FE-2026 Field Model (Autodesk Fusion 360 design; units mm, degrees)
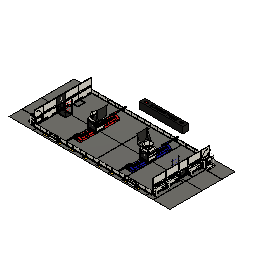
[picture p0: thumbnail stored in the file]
description: STEP AP242 Edition 2
part number: FE-2026: REBUILT
description: GE-26900: FUEL
part number: GE-26900: FUEL
description: BLOCK CAD: SCORING TABLE
part number: BLOCK CAD: SCORING TABLE
description: 100in Long 2in Wide White Gaff Tape
part number: 100in Long 2in Wide White Gaff Tape
description: FE-2026-01: Playing Field Carpet
part number: FE-2026-01: Playing Field Carpet
description: 17.625in Long 2in Wide Red Gaff Tape
part number: 17.625in Long 2in Wide Red Gaff Tape
description: 17.625in Long 2in Wide Blue Gaff Tape
part number: 17.625in Long 2in Wide Blue Gaff Tape
description: 317.187in Long 2in Wide Red Gaff Tape
part number: 317.187in Long 2in Wide Red Gaff Tape
description: 316.188in Long 2in Wide White Gaff Tape
part number: 316.188in Long 2in Wide White Gaff Tape
description: 289in Long 2in Wide White Gaff Tape
part number: 289in Long 2in Wide White Gaff Tape
base_feature "Base Feature1"
base_feature "Base Feature1"
base_feature "Base Feature1"
base_feature "Base Feature1"
base_feature "Base Feature1"
base_feature "Base Feature1"
base_feature "Base Feature1"
base_feature "Base Feature1"
base_feature "Base Feature1"
base_feature "Base Feature1"
base_feature "Base Feature1"
base_feature "Base Feature1"
base_feature "Base Feature1"
base_feature "Base Feature1"
base_feature "Base Feature1"
base_feature "Base Feature1"
base_feature "Base Feature1"
base_feature "Base Feature1"
base_feature "Base Feature1"
base_feature "Base Feature1"
base_feature "Base Feature1"
base_feature "Base Feature1"
base_feature "Base Feature1"
base_feature "Base Feature1"
base_feature "Base Feature1"
base_feature "Base Feature1"
base_feature "Base Feature1"
base_feature "Base Feature1"
base_feature "Base Feature1"
base_feature "Base Feature1"
base_feature "Base Feature1"
base_feature "Base Feature1"
base_feature "Base Feature1"
base_feature "Base Feature1"
base_feature "Base Feature1"
base_feature "Base Feature1"
base_feature "Base Feature1"
base_feature "Base Feature1"
base_feature "Base Feature1"
base_feature "Base Feature1"
base_feature "Base Feature1"
base_feature "Base Feature1"
base_feature "Base Feature1"
base_feature "Base Feature1"
base_feature "Base Feature1"
base_feature "Base Feature1"
base_feature "Base Feature1"
base_feature "Base Feature1"
base_feature "Base Feature1"
base_feature "Base Feature1"
base_feature "Base Feature1"
base_feature "Base Feature1"
base_feature "Base Feature1"
base_feature "Base Feature1"
base_feature "Base Feature1"
base_feature "Base Feature1"
base_feature "Base Feature1"
base_feature "Base Feature1"
base_feature "Base Feature1"
base_feature "Base Feature1"
base_feature "Base Feature1"
base_feature "Base Feature1"
base_feature "Base Feature1"
base_feature "Base Feature1"
base_feature "Base Feature1"
base_feature "Base Feature1"
base_feature "Base Feature1"
base_feature "Base Feature1"
base_feature "Base Feature1"
base_feature "Base Feature1"
base_feature "Base Feature1"
base_feature "Base Feature1"
base_feature "Base Feature1"
base_feature "Base Feature1"
base_feature "Base Feature1"
base_feature "Base Feature1"
base_feature "Base Feature1"
base_feature "Base Feature1"
base_feature "Base Feature1"
base_feature "Base Feature1"
base_feature "Base Feature1"
base_feature "Base Feature1"
base_feature "Base Feature1"
base_feature "Base Feature1"
base_feature "Base Feature1"
base_feature "Base Feature1"
base_feature "Base Feature1"
base_feature "Base Feature1"
base_feature "Base Feature1"
base_feature "Base Feature1"
base_feature "Base Feature1"
base_feature "Base Feature1"
base_feature "Base Feature1"
base_feature "Base Feature1"
base_feature "Base Feature1"
base_feature "Base Feature1"
base_feature "Base Feature1"
base_feature "Base Feature1"
base_feature "Base Feature1"
base_feature "Base Feature1"
base_feature "Base Feature1"
base_feature "Base Feature1"
base_feature "Base Feature1"
base_feature "Base Feature1"
base_feature "Base Feature1"
base_feature "Base Feature1"
base_feature "Base Feature1"
base_feature "Base Feature1"
base_feature "Base Feature1"
base_feature "Base Feature1"
base_feature "Base Feature1"
base_feature "Base Feature1"
base_feature "Base Feature1"
base_feature "Base Feature1"
base_feature "Base Feature1"
base_feature "Base Feature1"
base_feature "Base Feature1"
base_feature "Base Feature1"
base_feature "Base Feature1"
base_feature "Base Feature1"
base_feature "Base Feature1"
base_feature "Base Feature1"
base_feature "Base Feature1"
base_feature "Base Feature1"
base_feature "Base Feature1"
base_feature "Base Feature1"
base_feature "Base Feature1"
base_feature "Base Feature1"
base_feature "Base Feature1"
base_feature "Base Feature1"
base_feature "Base Feature1"
base_feature "Base Feature1"
base_feature "Base Feature1"
base_feature "Base Feature1"
base_feature "Base Feature1"
base_feature "Base Feature1"
base_feature "Base Feature1"
base_feature "Base Feature1"
base_feature "Base Feature1"
base_feature "Base Feature1"
base_feature "Base Feature1"
base_feature "Base Feature1"
base_feature "Base Feature1"
base_feature "Base Feature1"
base_feature "Base Feature1"
base_feature "Base Feature1"
base_feature "Base Feature1"
base_feature "Base Feature1"
base_feature "Base Feature1"
base_feature "Base Feature1"
base_feature "Base Feature1"
base_feature "Base Feature1"
base_feature "Base Feature1"
base_feature "Base Feature1"
base_feature "Base Feature1"
base_feature "Base Feature1"
base_feature "Base Feature1"
base_feature "Base Feature1"
base_feature "Base Feature1"
base_feature "Base Feature1"
base_feature "Base Feature1"
base_feature "Base Feature1"
base_feature "Base Feature1"
base_feature "Base Feature1"
base_feature "Base Feature1"
base_feature "Base Feature1"
base_feature "Base Feature1"
base_feature "Base Feature1"
base_feature "Base Feature1"
base_feature "Base Feature1"
base_feature "Base Feature1"
base_feature "Base Feature1"
base_feature "Base Feature1"
base_feature "Base Feature1"
base_feature "Base Feature1"
base_feature "Base Feature1"
base_feature "Base Feature1"
base_feature "Base Feature1"
base_feature "Base Feature1"
base_feature "Base Feature1"
base_feature "Base Feature1"
base_feature "Base Feature1"
base_feature "Base Feature1"
base_feature "Base Feature1"
base_feature "Base Feature1"
base_feature "Base Feature1"
base_feature "Base Feature1"
base_feature "Base Feature1"
base_feature "Base Feature1"
base_feature "Base Feature1"
base_feature "Base Feature1"
base_feature "Base Feature1"
base_feature "Base Feature1"
base_feature "Base Feature1"
base_feature "Base Feature1"
base_feature "Base Feature1"
base_feature "Base Feature1"
base_feature "Base Feature1"
base_feature "Base Feature1"
base_feature "Base Feature1"
base_feature "Base Feature1"
base_feature "Base Feature1"
base_feature "Base Feature1"
base_feature "Base Feature1"
base_feature "Base Feature1"
base_feature "Base Feature1"
base_feature "Base Feature1"
base_feature "Base Feature1"
base_feature "Base Feature1"
base_feature "Base Feature1"
base_feature "Base Feature1"
base_feature "Base Feature1"
base_feature "Base Feature1"
base_feature "Base Feature1"
base_feature "Base Feature1"
base_feature "Base Feature1"
base_feature "Base Feature1"
base_feature "Base Feature1"
base_feature "Base Feature1"
base_feature "Base Feature1"
base_feature "Base Feature1"
base_feature "Base Feature1"
base_feature "Base Feature1"
base_feature "Base Feature1"
base_feature "Base Feature1"
base_feature "Base Feature1"
base_feature "Base Feature1"
base_feature "Base Feature1"
base_feature "Base Feature1"
base_feature "Base Feature1"
base_feature "Base Feature1"
base_feature "Base Feature1"
base_feature "Base Feature1"
base_feature "Base Feature1"
base_feature "Base Feature1"
base_feature "Base Feature1"
base_feature "Base Feature1"
base_feature "Base Feature1"
base_feature "Base Feature1"
base_feature "Base Feature1"
base_feature "Base Feature1"
base_feature "Base Feature1"
base_feature "Base Feature1"
base_feature "Base Feature1"
base_feature "Base Feature1"
base_feature "Base Feature1"
base_feature "Base Feature1"
base_feature "Base Feature1"
base_feature "Base Feature1"
base_feature "Base Feature1"
base_feature "Base Feature1"
base_feature "Base Feature1"
base_feature "Base Feature1"
base_feature "Base Feature1"
base_feature "Base Feature1"
base_feature "Base Feature1"
base_feature "Base Feature1"
base_feature "Base Feature1"
base_feature "Base Feature1"
base_feature "Base Feature1"
base_feature "Base Feature1"
base_feature "Base Feature1"
base_feature "Base Feature1"
base_feature "Base Feature1"
base_feature "Base Feature1"
base_feature "Base Feature1"
base_feature "Base Feature1"
base_feature "Base Feature1"
base_feature "Base Feature1"
base_feature "Base Feature1"
base_feature "Base Feature1"
base_feature "Base Feature1"
base_feature "Base Feature1"
base_feature "Base Feature1"
base_feature "Base Feature1"
base_feature "Base Feature1"
base_feature "Base Feature1"
base_feature "Base Feature1"
base_feature "Base Feature1"
base_feature "Base Feature1"
base_feature "Base Feature1"
base_feature "Base Feature1"
base_feature "Base Feature1"
base_feature "Base Feature1"
base_feature "Base Feature1"
base_feature "Base Feature1"
base_feature "Base Feature1"
base_feature "Base Feature1"
base_feature "Base Feature1"
base_feature "Base Feature1"
base_feature "Base Feature1"
base_feature "Base Feature1"
base_feature "Base Feature1"
base_feature "Base Feature1"
base_feature "Base Feature1"
base_feature "Base Feature1"
base_feature "Base Feature1"
base_feature "Base Feature1"
base_feature "Base Feature1"
base_feature "Base Feature1"
base_feature "Base Feature1"
base_feature "Base Feature1"
base_feature "Base Feature1"
base_feature "Base Feature1"
base_feature "Base Feature1"
base_feature "Base Feature1"
base_feature "Base Feature1"
base_feature "Base Feature1"
base_feature "Base Feature1"
base_feature "Base Feature1"
base_feature "Base Feature1"
base_feature "Base Feature1"
base_feature "Base Feature1"
base_feature "Base Feature1"
base_feature "Base Feature1"
base_feature "Base Feature1"
base_feature "Base Feature1"
base_feature "Base Feature1"
base_feature "Base Feature1"
base_feature "Base Feature1"
base_feature "Base Feature1"
base_feature "Base Feature1"
base_feature "Base Feature1"
base_feature "Base Feature1"
base_feature "Base Feature1"
base_feature "Base Feature1"
base_feature "Base Feature1"
base_feature "Base Feature1"
base_feature "Base Feature1"
base_feature "Base Feature1"
base_feature "Base Feature1"
base_feature "Base Feature1"
base_feature "Base Feature1"
base_feature "Base Feature1"
base_feature "Base Feature1"
base_feature "Base Feature1"
base_feature "Base Feature1"
base_feature "Base Feature1"
base_feature "Base Feature1"
base_feature "Base Feature1"
base_feature "Base Feature1"
base_feature "Base Feature1"
base_feature "Base Feature1"
base_feature "Base Feature1"
base_feature "Base Feature1"
base_feature "Base Feature1"
base_feature "Base Feature1"
base_feature "Base Feature1"
base_feature "Base Feature1"
base_feature "Base Feature1"
base_feature "Base Feature1"
base_feature "Base Feature1"
base_feature "Base Feature1"
base_feature "Base Feature1"
base_feature "Base Feature1"
base_feature "Base Feature1"
base_feature "Base Feature1"
base_feature "Base Feature1"
base_feature "Base Feature1"
base_feature "Base Feature1"
base_feature "Base Feature1"
base_feature "Base Feature1"
base_feature "Base Feature1"
base_feature "Base Feature1"
base_feature "Base Feature1"
base_feature "Base Feature1"
base_feature "Base Feature1"
base_feature "Base Feature1"
base_feature "Base Feature1"
base_feature "Base Feature1"
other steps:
create_component "CreateComponent1"
create_component "CreateComponent2"
create_component "CreateComponent3"
create_component "CreateComponent4"
create_component "CreateComponent5"
create_component "CreateComponent6"
create_component "CreateComponent7"
create_component "CreateComponent8"
create_component "CreateComponent9"
create_component "CreateComponent10"
create_component "CreateComponent1"
create_component "CreateComponent1"
create_component "CreateComponent2"
create_component "CreateComponent2"
create_component "CreateComponent3"
create_component "CreateComponent11"
create_component "CreateComponent1"
create_component "CreateComponent1"
create_component "CreateComponent2"
create_component "CreateComponent12"
create_component "CreateComponent13"
create_component "CreateComponent1"
create_component "CreateComponent2"
create_component "CreateComponent3"
create_component "CreateComponent4"
create_component "CreateComponent5"
create_component "CreateComponent6"
create_component "CreateComponent7"
create_component "CreateComponent8"
create_component "CreateComponent9"
create_component "CreateComponent10"
create_component "CreateComponent11"
create_component "CreateComponent12"
create_component "CreateComponent13"
create_component "CreateComponent14"
create_component "CreateComponent15"
create_component "CreateComponent16"
create_component "CreateComponent17"
create_component "CreateComponent1"
create_component "CreateComponent18"
create_component "CreateComponent19"
create_component "CreateComponent20"
create_component "CreateComponent21"
create_component "CreateComponent22"
create_component "CreateComponent23"
create_component "CreateComponent24"
create_component "CreateComponent25"
create_component "CreateComponent26"
create_component "CreateComponent27"
create_component "CreateComponent28"
create_component "CreateComponent1"
create_component "CreateComponent2"
create_component "CreateComponent29"
create_component "CreateComponent1"
create_component "CreateComponent2"
create_component "CreateComponent3"
create_component "CreateComponent30"
create_component "CreateComponent1"
create_component "CreateComponent2"
create_component "CreateComponent31"
create_component "CreateComponent32"
create_component "CreateComponent33"
create_component "CreateComponent1"
create_component "CreateComponent2"
create_component "CreateComponent34"
create_component "CreateComponent35"
create_component "CreateComponent1"
create_component "CreateComponent2"
create_component "CreateComponent3"
create_component "CreateComponent4"
create_component "CreateComponent36"
create_component "CreateComponent1"
create_component "CreateComponent2"
create_component "CreateComponent3"
create_component "CreateComponent4"
create_component "CreateComponent37"
create_component "CreateComponent1"
create_component "CreateComponent14"
create_component "CreateComponent1"
create_component "CreateComponent2"
create_component "CreateComponent3"
create_component "CreateComponent1"
create_component "CreateComponent2"
create_component "CreateComponent3"
create_component "CreateComponent4"
create_component "CreateComponent1"
create_component "CreateComponent2"
create_component "CreateComponent5"
create_component "CreateComponent6"
create_component "CreateComponent7"
create_component "CreateComponent8"
create_component "CreateComponent9"
create_component "CreateComponent10"
create_component "CreateComponent1"
create_component "CreateComponent11"
create_component "CreateComponent12"
create_component "CreateComponent1"
create_component "CreateComponent4"
create_component "CreateComponent1"
create_component "CreateComponent2"
create_component "CreateComponent3"
create_component "CreateComponent4"
create_component "CreateComponent5"
create_component "CreateComponent15"
create_component "CreateComponent1"
create_component "CreateComponent2"
create_component "CreateComponent3"
create_component "CreateComponent4"
create_component "CreateComponent5"
create_component "CreateComponent6"
create_component "CreateComponent1"
create_component "CreateComponent2"
create_component "CreateComponent7"
create_component "CreateComponent8"
create_component "CreateComponent9"
create_component "CreateComponent1"
create_component "CreateComponent2"
create_component "CreateComponent10"
create_component "CreateComponent1"
create_component "CreateComponent11"
create_component "CreateComponent1"
create_component "CreateComponent2"
create_component "CreateComponent12"
create_component "CreateComponent13"
create_component "CreateComponent1"
create_component "CreateComponent2"
create_component "CreateComponent3"
create_component "CreateComponent4"
create_component "CreateComponent14"
create_component "CreateComponent15"
create_component "CreateComponent16"
create_component "CreateComponent1"
create_component "CreateComponent2"
create_component "CreateComponent3"
create_component "CreateComponent17"
create_component "CreateComponent18"
create_component "CreateComponent16"
create_component "CreateComponent1"
create_component "CreateComponent2"
create_component "CreateComponent1"
create_component "CreateComponent2"
create_component "CreateComponent3"
create_component "CreateComponent4"
create_component "CreateComponent5"
create_component "CreateComponent3"
create_component "CreateComponent1"
create_component "CreateComponent2"
create_component "CreateComponent3"
create_component "CreateComponent4"
create_component "CreateComponent5"
create_component "CreateComponent17"
create_component "CreateComponent1"
create_component "CreateComponent2"
create_component "CreateComponent3"
create_component "CreateComponent4"
create_component "CreateComponent5"
create_component "CreateComponent6"
create_component "CreateComponent7"
create_component "CreateComponent1"
create_component "CreateComponent8"
create_component "CreateComponent9"
create_component "CreateComponent10"
create_component "CreateComponent1"
create_component "CreateComponent11"
create_component "CreateComponent12"
create_component "CreateComponent13"
create_component "CreateComponent18"
create_component "CreateComponent1"
create_component "CreateComponent2"
create_component "CreateComponent3"
create_component "CreateComponent4"
create_component "CreateComponent5"
create_component "CreateComponent6"
create_component "CreateComponent7"
create_component "CreateComponent8"
create_component "CreateComponent9"
create_component "CreateComponent10"
create_component "CreateComponent11"
create_component "CreateComponent12"
create_component "CreateComponent13"
create_component "CreateComponent14"
create_component "CreateComponent15"
create_component "CreateComponent16"
create_component "CreateComponent17"
create_component "CreateComponent18"
create_component "CreateComponent19"
create_component "CreateComponent20"
create_component "CreateComponent21"
create_component "CreateComponent22"
create_component "CreateComponent1"
create_component "CreateComponent23"
create_component "CreateComponent24"
create_component "CreateComponent25"
create_component "CreateComponent26"
create_component "CreateComponent27"
create_component "CreateComponent28"
create_component "CreateComponent29"
create_component "CreateComponent30"
create_component "CreateComponent31"
create_component "CreateComponent1"
create_component "CreateComponent32"
create_component "CreateComponent1"
create_component "CreateComponent33"
create_component "CreateComponent1"
create_component "CreateComponent34"
create_component "CreateComponent35"
create_component "CreateComponent1"
create_component "CreateComponent36"
create_component "CreateComponent1"
create_component "CreateComponent2"
create_component "CreateComponent3"
create_component "CreateComponent4"
create_component "CreateComponent37"
create_component "CreateComponent38"
create_component "CreateComponent39"
create_component "CreateComponent40"
create_component "CreateComponent41"
create_component "CreateComponent1"
create_component "CreateComponent42"
create_component "CreateComponent43"
create_component "CreateComponent1"
create_component "CreateComponent44"
create_component "CreateComponent45"
create_component "CreateComponent46"
create_component "CreateComponent1"
create_component "CreateComponent47"
create_component "CreateComponent48"
create_component "CreateComponent49"
create_component "CreateComponent1"
create_component "CreateComponent50"
create_component "CreateComponent51"
create_component "CreateComponent1"
create_component "CreateComponent2"
create_component "CreateComponent52"
create_component "CreateComponent1"
create_component "CreateComponent53"
create_component "CreateComponent54"
create_component "CreateComponent1"
create_component "CreateComponent55"
create_component "CreateComponent1"
create_component "CreateComponent56"
create_component "CreateComponent1"
create_component "CreateComponent57"
create_component "CreateComponent1"
create_component "CreateComponent2"
create_component "CreateComponent3"
create_component "CreateComponent4"
create_component "CreateComponent58"
create_component "CreateComponent1"
create_component "CreateComponent59"
create_component "CreateComponent1"
create_component "CreateComponent60"
create_component "CreateComponent1"
create_component "CreateComponent61"
create_component "CreateComponent62"
create_component "CreateComponent63"
create_component "CreateComponent64"
create_component "CreateComponent1"
create_component "CreateComponent65"
create_component "CreateComponent1"
create_component "CreateComponent66"
create_component "CreateComponent67"
create_component "CreateComponent68"
create_component "CreateComponent69"
create_component "CreateComponent70"
create_component "CreateComponent71"
create_component "CreateComponent72"
create_component "CreateComponent73"
create_component "CreateComponent74"
create_component "CreateComponent75"
create_component "CreateComponent1"
create_component "CreateComponent2"
create_component "CreateComponent3"
create_component "CreateComponent4"
create_component "CreateComponent5"
create_component "CreateComponent6"
create_component "CreateComponent7"
create_component "CreateComponent8"
create_component "CreateComponent9"
create_component "CreateComponent10"
create_component "CreateComponent11"
create_component "CreateComponent12"
create_component "CreateComponent13"
create_component "CreateComponent14"
create_component "CreateComponent15"
create_component "CreateComponent16"
create_component "CreateComponent1"
create_component "CreateComponent2"
create_component "CreateComponent17"
create_component "CreateComponent18"
create_component "CreateComponent19"
create_component "CreateComponent20"
create_component "CreateComponent21"
create_component "CreateComponent22"
create_component "CreateComponent23"
create_component "CreateComponent1"
create_component "CreateComponent24"
create_component "CreateComponent25"
create_component "CreateComponent26"
create_component "CreateComponent27"
create_component "CreateComponent28"
create_component "CreateComponent29"
create_component "CreateComponent30"
create_component "CreateComponent31"
create_component "CreateComponent32"
create_component "CreateComponent33"
create_component "CreateComponent34"
create_component "CreateComponent35"
create_component "CreateComponent36"
create_component "CreateComponent37"
create_component "CreateComponent38"
create_component "CreateComponent39"
create_component "CreateComponent1"
create_component "CreateComponent40"
create_component "CreateComponent41"
create_component "CreateComponent42"
create_component "CreateComponent1"
create_component "CreateComponent43"
create_component "CreateComponent44"
create_component "CreateComponent45"
create_component "CreateComponent46"
create_component "CreateComponent47"
create_component "CreateComponent1"
create_component "CreateComponent2"
create_component "CreateComponent3"
create_component "CreateComponent4"
create_component "CreateComponent48"
create_component "CreateComponent1"
create_component "CreateComponent49"
create_component "CreateComponent50"
create_component "CreateComponent51"
create_component "CreateComponent52"
create_component "CreateComponent1"
create_component "CreateComponent2"
create_component "CreateComponent3"
create_component "CreateComponent53"
create_component "CreateComponent54"
create_component "CreateComponent1"
create_component "CreateComponent55"
create_component "CreateComponent1"
create_component "CreateComponent2"
create_component "CreateComponent3"
create_component "CreateComponent4"
create_component "CreateComponent5"
create_component "CreateComponent6"
create_component "CreateComponent7"
create_component "CreateComponent8"
create_component "CreateComponent9"
create_component "CreateComponent10"
create_component "CreateComponent11"
create_component "CreateComponent12"
create_component "CreateComponent13"
create_component "CreateComponent14"
create_component "CreateComponent15"
create_component "CreateComponent16"
create_component "CreateComponent17"
create_component "CreateComponent18"
create_component "CreateComponent19"
create_component "CreateComponent20"
create_component "CreateComponent21"
create_component "CreateComponent22"
create_component "CreateComponent23"
create_component "CreateComponent56"
create_component "CreateComponent57"
create_component "CreateComponent58"
create_component "CreateComponent59"
create_component "CreateComponent60"
create_component "CreateComponent1"
create_component "CreateComponent2"
create_component "CreateComponent61"
create_component "CreateComponent62"
create_component "CreateComponent63"
create_component "CreateComponent1"
create_component "CreateComponent76"
create_component "CreateComponent1"
create_component "CreateComponent2"
create_component "CreateComponent3"
create_component "CreateComponent4"
create_component "CreateComponent77"
create_component "CreateComponent78"
create_component "CreateComponent19"
create_component "CreateComponent1"
create_component "CreateComponent1"
create_component "CreateComponent2"
create_component "CreateComponent3"
create_component "CreateComponent4"
create_component "CreateComponent5"
create_component "CreateComponent2"
create_component "CreateComponent1"
create_component "CreateComponent2"
create_component "CreateComponent3"
create_component "CreateComponent4"
create_component "CreateComponent5"
create_component "CreateComponent20"
create_component "CreateComponent1"
create_component "CreateComponent1"
create_component "CreateComponent2"
create_component "CreateComponent3"
create_component "CreateComponent4"
create_component "CreateComponent5"
create_component "CreateComponent2"
create_component "CreateComponent1"
create_component "CreateComponent2"
create_component "CreateComponent3"
create_component "CreateComponent4"
create_component "CreateComponent5"
create_component "CreateComponent21"
create_component "CreateComponent1"
create_component "CreateComponent1"
create_component "CreateComponent2"
create_component "CreateComponent3"
create_component "CreateComponent1"
create_component "CreateComponent4"
create_component "CreateComponent5"
create_component "CreateComponent6"
create_component "CreateComponent1"
create_component "CreateComponent7"
create_component "CreateComponent8"
create_component "CreateComponent1"
create_component "CreateComponent9"
create_component "CreateComponent10"
create_component "CreateComponent11"
create_component "CreateComponent12"
create_component "CreateComponent1"
create_component "CreateComponent13"
create_component "CreateComponent14"
create_component "CreateComponent15"
create_component "CreateComponent16"
create_component "CreateComponent17"
create_component "CreateComponent1"
create_component "CreateComponent18"
create_component "CreateComponent19"
create_component "CreateComponent20"
create_component "CreateComponent21"
create_component "CreateComponent22"
create_component "CreateComponent23"
create_component "CreateComponent1"
create_component "CreateComponent24"
create_component "CreateComponent25"
create_component "CreateComponent26"
create_component "CreateComponent27"
create_component "CreateComponent28"
create_component "CreateComponent29"
create_component "CreateComponent30"
create_component "CreateComponent31"
create_component "CreateComponent32"
create_component "CreateComponent1"
create_component "CreateComponent33"
create_component "CreateComponent34"
create_component "CreateComponent35"
create_component "CreateComponent36"
create_component "CreateComponent37"
create_component "CreateComponent1"
create_component "CreateComponent2"
create_component "CreateComponent3"
create_component "CreateComponent4"
create_component "CreateComponent5"
create_component "CreateComponent6"
create_component "CreateComponent7"
create_component "CreateComponent8"
create_component "CreateComponent9"
create_component "CreateComponent10"
create_component "CreateComponent11"
create_component "CreateComponent12"
create_component "CreateComponent13"
create_component "CreateComponent14"
create_component "CreateComponent15"
create_component "CreateComponent16"
create_component "CreateComponent17"
create_component "CreateComponent18"
create_component "CreateComponent19"
create_component "CreateComponent20"
create_component "CreateComponent21"
create_component "CreateComponent22"
create_component "CreateComponent23"
create_component "CreateComponent24"
create_component "CreateComponent25"
create_component "CreateComponent26"
create_component "CreateComponent27"
create_component "CreateComponent28"
create_component "CreateComponent29"
create_component "CreateComponent30"
create_component "CreateComponent31"
create_component "CreateComponent38"
create_component "CreateComponent39"
create_component "CreateComponent22"
create_component "CreateComponent1"
create_component "CreateComponent1"
create_component "CreateComponent2"
create_component "CreateComponent3"
create_component "CreateComponent4"
create_component "CreateComponent5"
create_component "CreateComponent1"
create_component "CreateComponent2"
create_component "CreateComponent6"
create_component "CreateComponent7"
create_component "CreateComponent8"
create_component "CreateComponent1"
create_component "CreateComponent2"
create_component "CreateComponent3"
create_component "CreateComponent4"
create_component "CreateComponent9"
create_component "CreateComponent1"
create_component "CreateComponent10"
create_component "CreateComponent1"
create_component "CreateComponent11"
create_component "CreateComponent12"
create_component "CreateComponent13"
create_component "CreateComponent14"
create_component "CreateComponent1"
create_component "CreateComponent15"
create_component "CreateComponent16"
create_component "CreateComponent1"
create_component "CreateComponent2"
create_component "CreateComponent3"
create_component "CreateComponent4"
create_component "CreateComponent5"
create_component "CreateComponent6"
create_component "CreateComponent17"
create_component "CreateComponent18"
create_component "CreateComponent1"
create_component "CreateComponent2"
create_component "CreateComponent3"
create_component "CreateComponent4"
create_component "CreateComponent1"
create_component "CreateComponent5"
create_component "CreateComponent6"
create_component "CreateComponent1"
create_component "CreateComponent7"
create_component "CreateComponent1"
create_component "CreateComponent19"
create_component "CreateComponent1"
create_component "CreateComponent2"
create_component "CreateComponent3"
create_component "CreateComponent4"
create_component "CreateComponent1"
create_component "CreateComponent2"
create_component "CreateComponent3"
create_component "CreateComponent4"
create_component "CreateComponent5"
create_component "CreateComponent6"
create_component "CreateComponent7"
create_component "CreateComponent8"
create_component "CreateComponent20"
create_component "CreateComponent1"
create_component "CreateComponent2"
create_component "CreateComponent1"
create_component "CreateComponent1"
create_component "CreateComponent2"
create_component "CreateComponent3"
create_component "CreateComponent4"
create_component "CreateComponent1"
create_component "CreateComponent2"
create_component "CreateComponent5"
create_component "CreateComponent6"
create_component "CreateComponent7"
create_component "CreateComponent1"
create_component "CreateComponent8"
create_component "CreateComponent1"
create_component "CreateComponent1"
create_component "CreateComponent2"
create_component "CreateComponent1"
create_component "CreateComponent23"
create_component "CreateComponent1"
create_component "CreateComponent2"
create_component "CreateComponent3"
create_component "CreateComponent4"
create_component "CreateComponent1"
create_component "CreateComponent5"
create_component "CreateComponent1"
create_component "CreateComponent6"
create_component "CreateComponent7"
create_component "CreateComponent8"
create_component "CreateComponent1"
create_component "CreateComponent2"
create_component "CreateComponent3"
create_component "CreateComponent9"
create_component "CreateComponent10"
create_component "CreateComponent11"
create_component "CreateComponent24"
create_component "CreateComponent1"
create_component "CreateComponent1"
create_component "CreateComponent2"
create_component "CreateComponent3"
create_component "CreateComponent1"
create_component "CreateComponent4"
create_component "CreateComponent5"
create_component "CreateComponent1"
create_component "CreateComponent6"
create_component "CreateComponent7"
create_component "CreateComponent8"
create_component "CreateComponent9"
create_component "CreateComponent1"
create_component "CreateComponent10"
create_component "CreateComponent1"
create_component "CreateComponent2"
create_component "CreateComponent2"
create_component "CreateComponent1"
create_component "CreateComponent2"
create_component "CreateComponent3"
create_component "CreateComponent1"
create_component "CreateComponent4"
create_component "CreateComponent1"
create_component "CreateComponent5"
create_component "CreateComponent6"
create_component "CreateComponent7"
create_component "CreateComponent1"
create_component "CreateComponent2"
create_component "CreateComponent3"
create_component "CreateComponent4"
create_component "CreateComponent5"
create_component "CreateComponent6"
create_component "CreateComponent8"
create_component "CreateComponent9"
create_component "CreateComponent10"
create_component "CreateComponent11"
create_component "CreateComponent1"
create_component "CreateComponent2"
create_component "CreateComponent3"
create_component "CreateComponent12"
create_component "CreateComponent1"
create_component "CreateComponent25"
create_component "CreateComponent1"
create_component "CreateComponent1"
create_component "CreateComponent2"
create_component "CreateComponent2"
create_component "CreateComponent3"
create_component "CreateComponent4"
create_component "CreateComponent5"
create_component "CreateComponent6"
create_component "CreateComponent7"
create_component "CreateComponent8"
create_component "CreateComponent1"
create_component "CreateComponent2"
create_component "CreateComponent9"
create_component "CreateComponent10"
create_component "CreateComponent11"
create_component "CreateComponent12"
create_component "CreateComponent13"
create_component "CreateComponent14"
create_component "CreateComponent15"
create_component "CreateComponent1"
create_component "CreateComponent2"
create_component "CreateComponent1"
create_component "CreateComponent2"
create_component "CreateComponent3"
create_component "CreateComponent4"
create_component "CreateComponent5"
create_component "CreateComponent16"
create_component "CreateComponent1"
create_component "CreateComponent17"
create_component "CreateComponent18"
create_component "CreateComponent19"
create_component "CreateComponent1"
create_component "CreateComponent20"
create_component "CreateComponent1"
create_component "CreateComponent21"
create_component "CreateComponent1"
create_component "CreateComponent22"
create_component "CreateComponent1"
create_component "CreateComponent23"
create_component "CreateComponent1"
create_component "CreateComponent2"
create_component "CreateComponent3"
create_component "CreateComponent4"
create_component "CreateComponent5"
create_component "CreateComponent6"
create_component "CreateComponent7"
create_component "CreateComponent8"
create_component "CreateComponent24"
create_component "CreateComponent1"
create_component "CreateComponent2"
create_component "CreateComponent3"
create_component "CreateComponent4"
create_component "CreateComponent5"
create_component "CreateComponent6"
create_component "CreateComponent7"
create_component "CreateComponent8"
create_component "CreateComponent25"
create_component "CreateComponent1"
create_component "CreateComponent26"
create_component "CreateComponent1"
create_component "CreateComponent27"
create_component "CreateComponent28"
create_component "CreateComponent29"
create_component "CreateComponent30"
create_component "CreateComponent1"
create_component "CreateComponent1"
create_component "CreateComponent2"
create_component "CreateComponent2"
create_component "CreateComponent3"
create_component "CreateComponent1"
create_component "CreateComponent2"
create_component "CreateComponent3"
create_component "CreateComponent4"
create_component "CreateComponent4"
create_component "CreateComponent5"
create_component "CreateComponent1"
create_component "CreateComponent2"
create_component "CreateComponent3"
create_component "CreateComponent4"
create_component "CreateComponent6"
create_component "CreateComponent7"
create_component "CreateComponent1"
create_component "CreateComponent2"
create_component "CreateComponent3"
create_component "CreateComponent4"
create_component "CreateComponent1"
create_component "CreateComponent2"
create_component "CreateComponent3"
create_component "CreateComponent4"
create_component "CreateComponent5"
create_component "CreateComponent1"
create_component "CreateComponent2"
create_component "CreateComponent3"
create_component "CreateComponent6"
create_component "CreateComponent7"
create_component "CreateComponent8"
create_component "CreateComponent1"
create_component "CreateComponent2"
create_component "CreateComponent3"
create_component "CreateComponent4"
create_component "CreateComponent5"
create_component "CreateComponent6"
create_component "CreateComponent9"
create_component "CreateComponent1"
create_component "CreateComponent2"
create_component "CreateComponent3"
create_component "CreateComponent10"
create_component "CreateComponent11"
create_component "CreateComponent1"
create_component "CreateComponent2"
create_component "CreateComponent3"
create_component "CreateComponent12"
create_component "CreateComponent13"
create_component "CreateComponent31"
create_component "CreateComponent1"
create_component "CreateComponent2"
create_component "CreateComponent3"
create_component "CreateComponent4"
create_component "CreateComponent5"
create_component "CreateComponent1"
create_component "CreateComponent1"
create_component "CreateComponent2"
create_component "CreateComponent3"
create_component "CreateComponent4"
create_component "CreateComponent5"
create_component "CreateComponent6"
create_component "CreateComponent7"
create_component "CreateComponent32"
create_component "CreateComponent1"
create_component "CreateComponent2"
create_component "CreateComponent3"
create_component "CreateComponent1"
create_component "CreateComponent1"
create_component "CreateComponent2"
create_component "CreateComponent3"
create_component "CreateComponent4"
create_component "CreateComponent5"
create_component "CreateComponent6"
create_component "CreateComponent7"
create_component "CreateComponent4"
create_component "CreateComponent5"
create_component "CreateComponent33"
create_component "CreateComponent1"
create_component "CreateComponent2"
create_component "CreateComponent3"
create_component "CreateComponent4"
create_component "CreateComponent5"
create_component "CreateComponent1"
create_component "CreateComponent1"
create_component "CreateComponent2"
create_component "CreateComponent3"
create_component "CreateComponent4"
create_component "CreateComponent5"
create_component "CreateComponent6"
create_component "CreateComponent7"
create_component "CreateComponent34"
create_component "CreateComponent1"
create_component "CreateComponent2"
create_component "CreateComponent3"
create_component "CreateComponent4"
create_component "CreateComponent5"
create_component "CreateComponent1"
create_component "CreateComponent1"
create_component "CreateComponent2"
create_component "CreateComponent3"
create_component "CreateComponent4"
create_component "CreateComponent5"
create_component "CreateComponent6"
create_component "CreateComponent7"
create_component "CreateComponent35"
create_component "CreateComponent1"
create_component "CreateComponent2"
create_component "CreateComponent3"
create_component "CreateComponent1"
create_component "CreateComponent2"
create_component "CreateComponent4"
create_component "CreateComponent1"
create_component "CreateComponent2"
create_component "CreateComponent5"
create_component "CreateComponent1"
create_component "CreateComponent2"
create_component "CreateComponent6"
create_component "CreateComponent7"
create_component "CreateComponent8"
create_component "CreateComponent1"
create_component "CreateComponent9"
create_component "CreateComponent10"
create_component "CreateComponent11"
create_component "CreateComponent12"
create_component "CreateComponent13"
create_component "CreateComponent14"
create_component "CreateComponent15"
create_component "CreateComponent16"
create_component "CreateComponent17"
create_component "CreateComponent18"
create_component "CreateComponent19"
create_component "CreateComponent1"
create_component "CreateComponent2"
create_component "CreateComponent3"
create_component "CreateComponent4"
create_component "CreateComponent1"
create_component "CreateComponent2"
create_component "CreateComponent3"
create_component "CreateComponent5"
create_component "CreateComponent20"
create_component "CreateComponent21"
create_component "CreateComponent22"
create_component "CreateComponent23"
create_component "CreateComponent1"
create_component "CreateComponent24"
create_component "CreateComponent25"
create_component "CreateComponent1"
create_component "CreateComponent2"
create_component "CreateComponent3"
create_component "CreateComponent4"
create_component "CreateComponent5"
create_component "CreateComponent6"
create_component "CreateComponent7"
create_component "CreateComponent26"
create_component "CreateComponent27"
create_component "CreateComponent28"
create_component "CreateComponent29"
create_component "CreateComponent1"
create_component "CreateComponent2"
create_component "CreateComponent3"
create_component "CreateComponent4"
create_component "CreateComponent5"
create_component "CreateComponent6"
create_component "CreateComponent7"
create_component "CreateComponent8"
create_component "CreateComponent9"
create_component "CreateComponent10"
create_component "CreateComponent11"
create_component "CreateComponent12"
create_component "CreateComponent13"
create_component "CreateComponent14"
create_component "CreateComponent1"
create_component "CreateComponent2"
create_component "CreateComponent3"
create_component "CreateComponent4"
create_component "CreateComponent5"
create_component "CreateComponent6"
create_component "CreateComponent7"
create_component "CreateComponent8"
create_component "CreateComponent30"
create_component "CreateComponent1"
create_component "CreateComponent2"
create_component "CreateComponent3"
create_component "CreateComponent4"
create_component "CreateComponent5"
create_component "CreateComponent6"
create_component "CreateComponent7"
create_component "CreateComponent31"
create_component "CreateComponent32"
create_component "CreateComponent33"
create_component "CreateComponent34"
create_component "CreateComponent1"
create_component "CreateComponent35"
create_component "CreateComponent36"
create_component "CreateComponent37"
create_component "CreateComponent1"
create_component "CreateComponent1"
create_component "CreateComponent2"
create_component "CreateComponent3"
create_component "CreateComponent4"
create_component "CreateComponent5"
create_component "CreateComponent38"
create_component "CreateComponent39"
create_component "CreateComponent40"
create_component "CreateComponent1"
create_component "CreateComponent41"
create_component "CreateComponent1"
create_component "CreateComponent36"
create_component "CreateComponent1"
create_component "CreateComponent2"
create_component "CreateComponent3"
create_component "CreateComponent4"
create_component "CreateComponent1"
create_component "CreateComponent1"
create_component "CreateComponent2"
create_component "CreateComponent3"
create_component "CreateComponent4"
create_component "CreateComponent5"
create_component "CreateComponent6"
create_component "CreateComponent7"
create_component "CreateComponent5"
create_component "CreateComponent37"
create_component "CreateComponent1"
create_component "CreateComponent2"
create_component "CreateComponent3"
create_component "CreateComponent4"
create_component "CreateComponent5"
create_component "CreateComponent6"
create_component "CreateComponent7"
create_component "CreateComponent8"
create_component "CreateComponent9"
create_component "CreateComponent10"
create_component "CreateComponent11"
create_component "CreateComponent12"
create_component "CreateComponent13"
create_component "CreateComponent14"
create_component "CreateComponent15"
create_component "CreateComponent16"
create_component "CreateComponent17"
create_component "CreateComponent18"
create_component "CreateComponent19"
create_component "CreateComponent20"
create_component "CreateComponent21"
create_component "CreateComponent22"
create_component "CreateComponent23"
create_component "CreateComponent1"
create_component "CreateComponent24"
create_component "CreateComponent1"
create_component "CreateComponent25"
create_component "CreateComponent26"
create_component "CreateComponent27"
create_component "CreateComponent28"
create_component "CreateComponent29"
create_component "CreateComponent30"
create_component "CreateComponent31"
create_component "CreateComponent1"
create_component "CreateComponent32"
create_component "CreateComponent33"
create_component "CreateComponent1"
create_component "CreateComponent34"
create_component "CreateComponent35"
create_component "CreateComponent36"
create_component "CreateComponent1"
create_component "CreateComponent37"
create_component "CreateComponent38"
create_component "CreateComponent1"
create_component "CreateComponent39"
